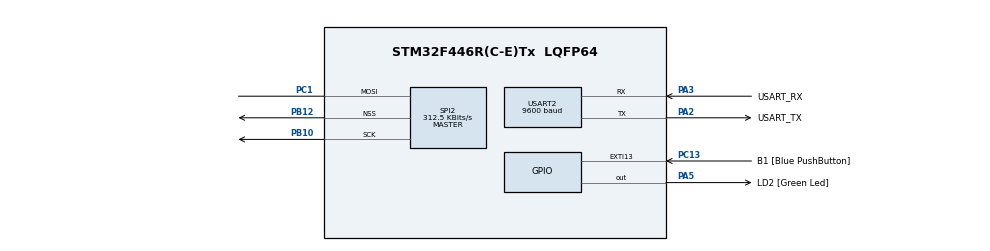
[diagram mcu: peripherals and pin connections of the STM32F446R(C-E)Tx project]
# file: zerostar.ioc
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Mcu.Family=STM32F4
Mcu.Name=STM32F446R(C-E)Tx
Mcu.Package=LQFP64
NVIC.PriorityGroup=NVIC_PRIORITYGROUP_0
PA13.GPIO_Label=TMS
PA13.Mode=Serial_Wire
PA13.Signal=SYS_JTMS-SWDIO
PA14.GPIO_Label=TCK
PA14.Mode=Serial_Wire
PA14.Signal=SYS_JTCK-SWCLK
PA2.GPIO_Label=USART_TX
PA2.Mode=Asynchronous
PA2.Signal=USART2_TX
PA3.GPIO_Label=USART_RX
PA3.Mode=Asynchronous
PA3.Signal=USART2_RX
PA5.GPIO_Label=LD2 [Green Led]
PA5.Signal=GPIO_Output
PB10.Mode=Simplex_Bidirectional_Master
PB10.Signal=SPI2_SCK
PB12.Mode=NSS_Signal_Hard_Output
PB12.Signal=SPI2_NSS
PB3.GPIO_Label=SWO
PB3.Signal=SYS_JTDO-SWO
PC1.Mode=Simplex_Bidirectional_Master
PC1.Signal=SPI2_MOSI
PC13.GPIO_Label=B1 [Blue PushButton]
PC13.GPIO_ModeDefaultEXTI=GPIO_MODE_IT_FALLING
PC13.Signal=GPXTI13
PC14-OSC32_IN.Mode=LSE-External-Oscillator
PC14-OSC32_IN.Signal=RCC_OSC32_IN
PC15-OSC32_OUT.Mode=LSE-External-Oscillator
PC15-OSC32_OUT.Signal=RCC_OSC32_OUT
PH0-OSC_IN.Mode=HSE-External-Clock-Source
PH0-OSC_IN.Signal=RCC_OSC_IN
PH1-OSC_OUT.Mode=HSE-External-Clock-Source
PH1-OSC_OUT.Signal=RCC_OSC_OUT
ProjectManager.HeapSize=0x200
ProjectManager.StackSize=0x400
ProjectManager.TargetToolchain=STM32CubeIDE
RCC.48MHZClocksFreq_Value=84000000
RCC.AHBCLKDivider=RCC_SYSCLK_DIV8
RCC.AHBFreq_Value=10000000
RCC.APB1CLKDivider=RCC_HCLK_DIV16
RCC.APB1Freq_Value=625000
RCC.APB1TimFreq_Value=1250000
RCC.APB2CLKDivider=RCC_HCLK_DIV16
RCC.APB2Freq_Value=625000
RCC.APB2TimFreq_Value=1250000
RCC.CortexFreq_Value=10000000
RCC.FLatency-AdvancedSettings=FLASH_LATENCY_0
RCC.HCLKFreq_Value=10000000
RCC.HSE_VALUE=8000000
RCC.HSI_VALUE=16000000
RCC.PLLM=8
RCC.PLLN=80
RCC.SYSCLKFreq_VALUE=80000000
RCC.SYSCLKSource=RCC_SYSCLKSOURCE_PLLCLK
RCC.USBFreq_Value=80000000
RCC.VCOOutputFreq_Value=160000000
SPI2.CalculateBaudRate=312.5 KBits/s
SPI2.DataSize=SPI_DATASIZE_16BIT
SPI2.Direction=SPI_DIRECTION_1LINE
SPI2.Mode=SPI_MODE_MASTER
SPI2.VirtualNSS=VM_NSSHARD
SPI2.VirtualType=VM_MASTER
USART2.BaudRate=9600
USART2.VirtualMode=VM_ASYNC
board=NUCLEO-F446RE

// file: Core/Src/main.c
/* USER CODE BEGIN Header */
/**
  ******************************************************************************
  * @file           : main.c
  * @brief          : Main program body
  ******************************************************************************
  * @attention
  *
  * <h2><center>&copy; Copyright (c) 2019 STMicroelectronics.
  * All rights reserved.</center></h2>
  *
  * This software component is licensed by ST under BSD 3-Clause license,
  * the "License"; You may not use this file except in compliance with the
  * License. You may obtain a copy of the License at:
  *                        opensource.org/licenses/BSD-3-Clause
  *
  ******************************************************************************
  */
/* USER CODE END Header */

#include "main.h"

/* USER CODE BEGIN Includes */
#define MAX7219_MODE_DECODE       0x0900
#define MAX7219_MODE_INTENSITY    0x0A00
#define MAX7219_MODE_SCAN_LIMIT   0x0B00
#define MAX7219_MODE_POWER        0x0C00
#define MAX7219_MODE_TEST         0x0F00
#define MAX7219_MODE_NOOP         0x0000

//#define __SPI_CS_ENABLE__() do {    HAL_GPIO_WritePin(GPIOB, GPIO_PIN_15, GPIO_PIN_RESET);   } while(0)
//#define __SPI_CS_DISABLE__() do {   HAL_GPIO_WritePin(GPIOB, GPIO_PIN_15, GPIO_PIN_SET);     } while(0)
//   __HAL_AFIO_REMAP_SPI2_DISABLE(); // No remap (NSS/PA4, SCK/PA5, MISO/PA6, MOSI/PA7)

/* USER CODE END Includes */

SPI_HandleTypeDef hspi2;

UART_HandleTypeDef huart2;

void SystemClock_Config(void);
static void MX_GPIO_Init(void);
static void MX_USART2_UART_Init(void);
static void MX_SPI2_Init(void);
/* USER CODE BEGIN PFP */
void SPI_Transmit(SPI_HandleTypeDef *hspi, uint16_t data) {
    // 2nd parameter - pData: pointer to data buffer
    HAL_SPI_Transmit(hspi, (uint8_t *) &data, 1, 1000);
    HAL_GPIO_WritePin(GPIOB, GPIO_PIN_12, GPIO_PIN_SET);
}

/* USER CODE END PFP */

int main(void)
{

  /* MCU Configuration--------------------------------------------------------*/

  /* Reset of all peripherals, Initializes the Flash interface and the Systick. */
  HAL_Init();

  /* Configure the system clock */
  SystemClock_Config();

  /* Initialize all configured peripherals */
  MX_GPIO_Init();
  MX_USART2_UART_Init();
  MX_SPI2_Init();
// __HAL_SPI_ENABLE(&hspi2);

      // CS inactive

      // Init MAX7219
         SPI_Transmit(&hspi2, MAX7219_MODE_SCAN_LIMIT | 0x7);

      SPI_Transmit(&hspi2, MAX7219_MODE_INTENSITY | 0xF0);

      SPI_Transmit(&hspi2, MAX7219_MODE_POWER | 0x11);

      SPI_Transmit(&hspi2, MAX7219_MODE_DECODE | 0x01);

  /* Infinite loop */
  while (1)
  {

    /* USER CODE BEGIN 3 */
   HAL_GPIO_TogglePin(GPIOC, GPIO_PIN_13);

  uint16_t col;
  int bit;

  for (col = 0x100; col <= 0x800; col += 0x100) {
      for (bit = 7; bit >= 0; bit--) {

          SPI_Transmit(&hspi2, col | (1 << bit & 0xFF));
          HAL_Delay(30);
      }
  }
  /* USER CODE END 3 */
}
}

void SystemClock_Config(void)
{
  RCC_OscInitTypeDef RCC_OscInitStruct = {0};
  RCC_ClkInitTypeDef RCC_ClkInitStruct = {0};

  /** Configure the main internal regulator output voltage
  */
  __HAL_RCC_PWR_CLK_ENABLE();
  __HAL_PWR_VOLTAGESCALING_CONFIG(PWR_REGULATOR_VOLTAGE_SCALE3);
  /** Initializes the CPU, AHB and APB busses clocks
  */
  RCC_OscInitStruct.OscillatorType = RCC_OSCILLATORTYPE_HSI;
  RCC_OscInitStruct.HSIState = RCC_HSI_ON;
  RCC_OscInitStruct.HSICalibrationValue = RCC_HSICALIBRATION_DEFAULT;
  RCC_OscInitStruct.PLL.PLLState = RCC_PLL_ON;
  RCC_OscInitStruct.PLL.PLLSource = RCC_PLLSOURCE_HSI;
  RCC_OscInitStruct.PLL.PLLM = 8;
  RCC_OscInitStruct.PLL.PLLN = 80;
  RCC_OscInitStruct.PLL.PLLP = RCC_PLLP_DIV2;
  RCC_OscInitStruct.PLL.PLLQ = 2;
  RCC_OscInitStruct.PLL.PLLR = 2;
  if (HAL_RCC_OscConfig(&RCC_OscInitStruct) != HAL_OK)
  {
    Error_Handler();
  }
  /** Initializes the CPU, AHB and APB busses clocks
  */
  RCC_ClkInitStruct.ClockType = RCC_CLOCKTYPE_HCLK|RCC_CLOCKTYPE_SYSCLK
                              |RCC_CLOCKTYPE_PCLK1|RCC_CLOCKTYPE_PCLK2;
  RCC_ClkInitStruct.SYSCLKSource = RCC_SYSCLKSOURCE_PLLCLK;
  RCC_ClkInitStruct.AHBCLKDivider = RCC_SYSCLK_DIV1;
  RCC_ClkInitStruct.APB1CLKDivider = RCC_HCLK_DIV16;
  RCC_ClkInitStruct.APB2CLKDivider = RCC_HCLK_DIV16;

  if (HAL_RCC_ClockConfig(&RCC_ClkInitStruct, FLASH_LATENCY_2) != HAL_OK)
  {
    Error_Handler();
  }
}

static void MX_SPI2_Init(void)
{

  /* SPI2 parameter configuration*/
  hspi2.Instance = SPI2;
  hspi2.Init.Mode = SPI_MODE_MASTER;
  hspi2.Init.Direction = SPI_DIRECTION_1LINE;
  hspi2.Init.DataSize = SPI_DATASIZE_16BIT;
  hspi2.Init.CLKPolarity = SPI_POLARITY_LOW;
  hspi2.Init.CLKPhase = SPI_PHASE_1EDGE;
  hspi2.Init.NSS = SPI_NSS_HARD_OUTPUT;
  hspi2.Init.BaudRatePrescaler = SPI_BAUDRATEPRESCALER_2;
  hspi2.Init.FirstBit = SPI_FIRSTBIT_MSB;
  hspi2.Init.TIMode = SPI_TIMODE_DISABLE;
  hspi2.Init.CRCCalculation = SPI_CRCCALCULATION_DISABLE;
  hspi2.Init.CRCPolynomial = 7;
  if (HAL_SPI_Init(&hspi2) != HAL_OK)
  {
    Error_Handler();
  }

}

static void MX_USART2_UART_Init(void)
{

  huart2.Instance = USART2;
  huart2.Init.BaudRate = 115200;
  huart2.Init.WordLength = UART_WORDLENGTH_8B;
  huart2.Init.StopBits = UART_STOPBITS_1;
  huart2.Init.Parity = UART_PARITY_NONE;
  huart2.Init.Mode = UART_MODE_TX_RX;
  huart2.Init.HwFlowCtl = UART_HWCONTROL_NONE;
  huart2.Init.OverSampling = UART_OVERSAMPLING_16;
  if (HAL_UART_Init(&huart2) != HAL_OK)
  {
    Error_Handler();
  }

}

static void MX_GPIO_Init(void)
{
  GPIO_InitTypeDef GPIO_InitStruct = {0};

  /* GPIO Ports Clock Enable */
  __HAL_RCC_GPIOC_CLK_ENABLE();
  __HAL_RCC_GPIOH_CLK_ENABLE();
  __HAL_RCC_GPIOA_CLK_ENABLE();
  __HAL_RCC_GPIOB_CLK_ENABLE();

  /*Configure GPIO pin Output Level */
  HAL_GPIO_WritePin(LD2_GPIO_Port, LD2_Pin, GPIO_PIN_RESET);

  /*Configure GPIO pin : B1_Pin */
  GPIO_InitStruct.Pin = B1_Pin;
  GPIO_InitStruct.Mode = GPIO_MODE_IT_FALLING;
  GPIO_InitStruct.Pull = GPIO_NOPULL;
  HAL_GPIO_Init(B1_GPIO_Port, &GPIO_InitStruct);

  /*Configure GPIO pin : LD2_Pin */
  GPIO_InitStruct.Pin = LD2_Pin;
  GPIO_InitStruct.Mode = GPIO_MODE_OUTPUT_PP;
  GPIO_InitStruct.Pull = GPIO_NOPULL;
  GPIO_InitStruct.Speed = GPIO_SPEED_FREQ_LOW;
  HAL_GPIO_Init(LD2_GPIO_Port, &GPIO_InitStruct);

//  GPIO_InitStruct.Pin = CS_Pin;
//  GPIO_InitStruct.Mode = GPIO_MODE_OUTPUT_PP;
//  GPIO_InitStruct.Pull = GPIO_NOPULL;
//  GPIO_InitStruct.Speed = GPIO_SPEED_FREQ_VERY_HIGH;
//  HAL_GPIO_Init(CS_GPIO_Port, &GPIO_InitStruct);
}

void Error_Handler(void)
{
}

/************************ (C) COPYRIGHT STMicroelectronics *****END OF FILE****/
